# Generated by OpenFakeRAM
VERSION 5.7 ;
BUSBITCHARS "[]" ;
PROPERTYDEFINITIONS
  MACRO width INTEGER ;
  MACRO depth INTEGER ;
  MACRO banks INTEGER ;
END PROPERTYDEFINITIONS
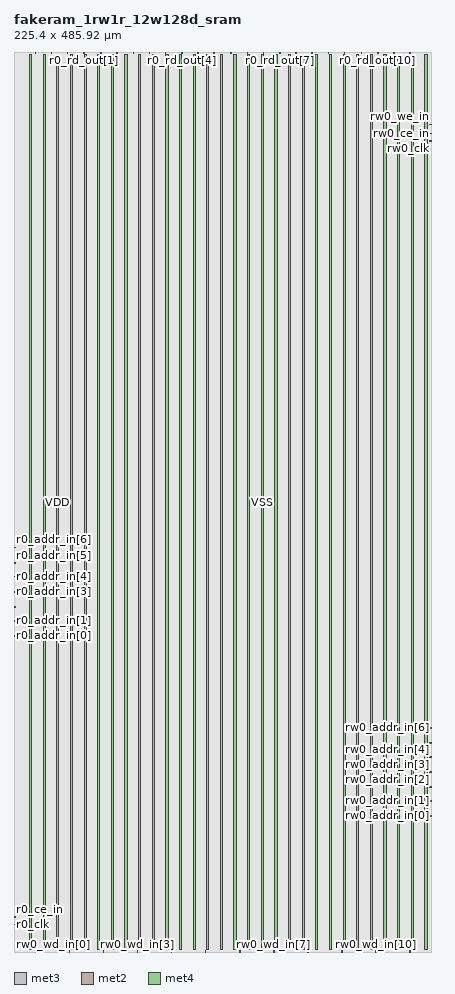
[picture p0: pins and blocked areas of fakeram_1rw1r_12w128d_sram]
MACRO fakeram_1rw1r_12w128d_sram
  PROPERTY width 12 ;
  PROPERTY depth 128 ;
  PROPERTY banks 1 ;
  FOREIGN fakeram_1rw1r_12w128d_sram 0 0 ;
  SYMMETRY X Y R90 ;
  SIZE 225.400 BY 485.920 ;
  CLASS BLOCK ;
  PIN r0_clk
    DIRECTION INPUT ;
    USE SIGNAL ;
    SHAPE ABUTMENT ;
    PORT
      LAYER met3 ;
      RECT 0.000 14.810 0.800 15.110 ;
    END
  END r0_clk
  PIN r0_ce_in
    DIRECTION INPUT ;
    USE SIGNAL ;
    SHAPE ABUTMENT ;
    PORT
      LAYER met3 ;
      RECT 0.000 18.890 0.800 19.190 ;
    END
  END r0_ce_in
  PIN r0_addr_in[0]
    DIRECTION INPUT ;
    USE SIGNAL ;
    SHAPE ABUTMENT ;
    PORT
      LAYER met3 ;
      RECT 0.000 170.530 0.800 170.830 ;
    END
  END r0_addr_in[0]
  PIN r0_addr_in[1]
    DIRECTION INPUT ;
    USE SIGNAL ;
    SHAPE ABUTMENT ;
    PORT
      LAYER met3 ;
      RECT 0.000 178.690 0.800 178.990 ;
    END
  END r0_addr_in[1]
  PIN r0_addr_in[2]
    DIRECTION INPUT ;
    USE SIGNAL ;
    SHAPE ABUTMENT ;
    PORT
      LAYER met3 ;
      RECT 0.000 186.170 0.800 186.470 ;
    END
  END r0_addr_in[2]
  PIN r0_addr_in[3]
    DIRECTION INPUT ;
    USE SIGNAL ;
    SHAPE ABUTMENT ;
    PORT
      LAYER met3 ;
      RECT 0.000 194.330 0.800 194.630 ;
    END
  END r0_addr_in[3]
  PIN r0_addr_in[4]
    DIRECTION INPUT ;
    USE SIGNAL ;
    SHAPE ABUTMENT ;
    PORT
      LAYER met3 ;
      RECT 0.000 202.490 0.800 202.790 ;
    END
  END r0_addr_in[4]
  PIN r0_addr_in[5]
    DIRECTION INPUT ;
    USE SIGNAL ;
    SHAPE ABUTMENT ;
    PORT
      LAYER met3 ;
      RECT 0.000 209.970 0.800 210.270 ;
    END
  END r0_addr_in[5]
  PIN r0_addr_in[6]
    DIRECTION INPUT ;
    USE SIGNAL ;
    SHAPE ABUTMENT ;
    PORT
      LAYER met3 ;
      RECT 0.000 218.130 0.800 218.430 ;
    END
  END r0_addr_in[6]
  PIN rw0_rd_out[0]
    DIRECTION OUTPUT ;
    USE SIGNAL ;
    SHAPE ABUTMENT ;
    PORT
      LAYER met2 ;
      RECT 11.350 485.120 11.650 485.920 ;
    END
  END rw0_rd_out[0]
  PIN r0_rd_out[0]
    DIRECTION OUTPUT ;
    USE SIGNAL ;
    SHAPE ABUTMENT ;
    PORT
      LAYER met2 ;
      RECT 20.090 485.120 20.390 485.920 ;
    END
  END r0_rd_out[0]
  PIN rw0_rd_out[1]
    DIRECTION OUTPUT ;
    USE SIGNAL ;
    SHAPE ABUTMENT ;
    PORT
      LAYER met2 ;
      RECT 28.830 485.120 29.130 485.920 ;
    END
  END rw0_rd_out[1]
  PIN r0_rd_out[1]
    DIRECTION OUTPUT ;
    USE SIGNAL ;
    SHAPE ABUTMENT ;
    PORT
      LAYER met2 ;
      RECT 37.570 485.120 37.870 485.920 ;
    END
  END r0_rd_out[1]
  PIN rw0_rd_out[2]
    DIRECTION OUTPUT ;
    USE SIGNAL ;
    SHAPE ABUTMENT ;
    PORT
      LAYER met2 ;
      RECT 46.770 485.120 47.070 485.920 ;
    END
  END rw0_rd_out[2]
  PIN r0_rd_out[2]
    DIRECTION OUTPUT ;
    USE SIGNAL ;
    SHAPE ABUTMENT ;
    PORT
      LAYER met2 ;
      RECT 55.510 485.120 55.810 485.920 ;
    END
  END r0_rd_out[2]
  PIN rw0_rd_out[3]
    DIRECTION OUTPUT ;
    USE SIGNAL ;
    SHAPE ABUTMENT ;
    PORT
      LAYER met2 ;
      RECT 64.250 485.120 64.550 485.920 ;
    END
  END rw0_rd_out[3]
  PIN r0_rd_out[3]
    DIRECTION OUTPUT ;
    USE SIGNAL ;
    SHAPE ABUTMENT ;
    PORT
      LAYER met2 ;
      RECT 72.990 485.120 73.290 485.920 ;
    END
  END r0_rd_out[3]
  PIN rw0_rd_out[4]
    DIRECTION OUTPUT ;
    USE SIGNAL ;
    SHAPE ABUTMENT ;
    PORT
      LAYER met2 ;
      RECT 81.730 485.120 82.030 485.920 ;
    END
  END rw0_rd_out[4]
  PIN r0_rd_out[4]
    DIRECTION OUTPUT ;
    USE SIGNAL ;
    SHAPE ABUTMENT ;
    PORT
      LAYER met2 ;
      RECT 90.470 485.120 90.770 485.920 ;
    END
  END r0_rd_out[4]
  PIN rw0_rd_out[5]
    DIRECTION OUTPUT ;
    USE SIGNAL ;
    SHAPE ABUTMENT ;
    PORT
      LAYER met2 ;
      RECT 99.210 485.120 99.510 485.920 ;
    END
  END rw0_rd_out[5]
  PIN r0_rd_out[5]
    DIRECTION OUTPUT ;
    USE SIGNAL ;
    SHAPE ABUTMENT ;
    PORT
      LAYER met2 ;
      RECT 107.950 485.120 108.250 485.920 ;
    END
  END r0_rd_out[5]
  PIN rw0_rd_out[6]
    DIRECTION OUTPUT ;
    USE SIGNAL ;
    SHAPE ABUTMENT ;
    PORT
      LAYER met2 ;
      RECT 117.150 485.120 117.450 485.920 ;
    END
  END rw0_rd_out[6]
  PIN r0_rd_out[6]
    DIRECTION OUTPUT ;
    USE SIGNAL ;
    SHAPE ABUTMENT ;
    PORT
      LAYER met2 ;
      RECT 125.890 485.120 126.190 485.920 ;
    END
  END r0_rd_out[6]
  PIN rw0_rd_out[7]
    DIRECTION OUTPUT ;
    USE SIGNAL ;
    SHAPE ABUTMENT ;
    PORT
      LAYER met2 ;
      RECT 134.630 485.120 134.930 485.920 ;
    END
  END rw0_rd_out[7]
  PIN r0_rd_out[7]
    DIRECTION OUTPUT ;
    USE SIGNAL ;
    SHAPE ABUTMENT ;
    PORT
      LAYER met2 ;
      RECT 143.370 485.120 143.670 485.920 ;
    END
  END r0_rd_out[7]
  PIN rw0_rd_out[8]
    DIRECTION OUTPUT ;
    USE SIGNAL ;
    SHAPE ABUTMENT ;
    PORT
      LAYER met2 ;
      RECT 152.110 485.120 152.410 485.920 ;
    END
  END rw0_rd_out[8]
  PIN r0_rd_out[8]
    DIRECTION OUTPUT ;
    USE SIGNAL ;
    SHAPE ABUTMENT ;
    PORT
      LAYER met2 ;
      RECT 160.850 485.120 161.150 485.920 ;
    END
  END r0_rd_out[8]
  PIN rw0_rd_out[9]
    DIRECTION OUTPUT ;
    USE SIGNAL ;
    SHAPE ABUTMENT ;
    PORT
      LAYER met2 ;
      RECT 169.590 485.120 169.890 485.920 ;
    END
  END rw0_rd_out[9]
  PIN r0_rd_out[9]
    DIRECTION OUTPUT ;
    USE SIGNAL ;
    SHAPE ABUTMENT ;
    PORT
      LAYER met2 ;
      RECT 178.330 485.120 178.630 485.920 ;
    END
  END r0_rd_out[9]
  PIN rw0_rd_out[10]
    DIRECTION OUTPUT ;
    USE SIGNAL ;
    SHAPE ABUTMENT ;
    PORT
      LAYER met2 ;
      RECT 187.530 485.120 187.830 485.920 ;
    END
  END rw0_rd_out[10]
  PIN r0_rd_out[10]
    DIRECTION OUTPUT ;
    USE SIGNAL ;
    SHAPE ABUTMENT ;
    PORT
      LAYER met2 ;
      RECT 196.270 485.120 196.570 485.920 ;
    END
  END r0_rd_out[10]
  PIN rw0_rd_out[11]
    DIRECTION OUTPUT ;
    USE SIGNAL ;
    SHAPE ABUTMENT ;
    PORT
      LAYER met2 ;
      RECT 205.010 485.120 205.310 485.920 ;
    END
  END rw0_rd_out[11]
  PIN r0_rd_out[11]
    DIRECTION OUTPUT ;
    USE SIGNAL ;
    SHAPE ABUTMENT ;
    PORT
      LAYER met2 ;
      RECT 213.750 485.120 214.050 485.920 ;
    END
  END r0_rd_out[11]
  PIN rw0_clk
    DIRECTION INPUT ;
    USE SIGNAL ;
    SHAPE ABUTMENT ;
    PORT
      LAYER met3 ;
      RECT 224.600 437.770 225.400 438.070 ;
    END
  END rw0_clk
  PIN rw0_ce_in
    DIRECTION INPUT ;
    USE SIGNAL ;
    SHAPE ABUTMENT ;
    PORT
      LAYER met3 ;
      RECT 224.600 441.850 225.400 442.150 ;
    END
  END rw0_ce_in
  PIN rw0_we_in
    DIRECTION INPUT ;
    USE SIGNAL ;
    SHAPE ABUTMENT ;
    PORT
      LAYER met3 ;
      RECT 224.600 446.610 225.400 446.910 ;
    END
  END rw0_we_in
  PIN rw0_addr_in[0]
    DIRECTION INPUT ;
    USE SIGNAL ;
    SHAPE ABUTMENT ;
    PORT
      LAYER met3 ;
      RECT 224.600 73.290 225.400 73.590 ;
    END
  END rw0_addr_in[0]
  PIN rw0_addr_in[1]
    DIRECTION INPUT ;
    USE SIGNAL ;
    SHAPE ABUTMENT ;
    PORT
      LAYER met3 ;
      RECT 224.600 81.450 225.400 81.750 ;
    END
  END rw0_addr_in[1]
  PIN rw0_addr_in[2]
    DIRECTION INPUT ;
    USE SIGNAL ;
    SHAPE ABUTMENT ;
    PORT
      LAYER met3 ;
      RECT 224.600 88.930 225.400 89.230 ;
    END
  END rw0_addr_in[2]
  PIN rw0_addr_in[3]
    DIRECTION INPUT ;
    USE SIGNAL ;
    SHAPE ABUTMENT ;
    PORT
      LAYER met3 ;
      RECT 224.600 97.090 225.400 97.390 ;
    END
  END rw0_addr_in[3]
  PIN rw0_addr_in[4]
    DIRECTION INPUT ;
    USE SIGNAL ;
    SHAPE ABUTMENT ;
    PORT
      LAYER met3 ;
      RECT 224.600 105.250 225.400 105.550 ;
    END
  END rw0_addr_in[4]
  PIN rw0_addr_in[5]
    DIRECTION INPUT ;
    USE SIGNAL ;
    SHAPE ABUTMENT ;
    PORT
      LAYER met3 ;
      RECT 224.600 112.730 225.400 113.030 ;
    END
  END rw0_addr_in[5]
  PIN rw0_addr_in[6]
    DIRECTION INPUT ;
    USE SIGNAL ;
    SHAPE ABUTMENT ;
    PORT
      LAYER met3 ;
      RECT 224.600 120.890 225.400 121.190 ;
    END
  END rw0_addr_in[6]
  PIN rw0_wd_in[0]
    DIRECTION INPUT ;
    USE SIGNAL ;
    SHAPE ABUTMENT ;
    PORT
      LAYER met2 ;
      RECT 11.350 0.000 11.650 0.800 ;
    END
  END rw0_wd_in[0]
  PIN rw0_wd_in[1]
    DIRECTION INPUT ;
    USE SIGNAL ;
    SHAPE ABUTMENT ;
    PORT
      LAYER met2 ;
      RECT 29.750 0.000 30.050 0.800 ;
    END
  END rw0_wd_in[1]
  PIN rw0_wd_in[2]
    DIRECTION INPUT ;
    USE SIGNAL ;
    SHAPE ABUTMENT ;
    PORT
      LAYER met2 ;
      RECT 48.150 0.000 48.450 0.800 ;
    END
  END rw0_wd_in[2]
  PIN rw0_wd_in[3]
    DIRECTION INPUT ;
    USE SIGNAL ;
    SHAPE ABUTMENT ;
    PORT
      LAYER met2 ;
      RECT 66.550 0.000 66.850 0.800 ;
    END
  END rw0_wd_in[3]
  PIN rw0_wd_in[4]
    DIRECTION INPUT ;
    USE SIGNAL ;
    SHAPE ABUTMENT ;
    PORT
      LAYER met2 ;
      RECT 84.950 0.000 85.250 0.800 ;
    END
  END rw0_wd_in[4]
  PIN rw0_wd_in[5]
    DIRECTION INPUT ;
    USE SIGNAL ;
    SHAPE ABUTMENT ;
    PORT
      LAYER met2 ;
      RECT 103.350 0.000 103.650 0.800 ;
    END
  END rw0_wd_in[5]
  PIN rw0_wd_in[6]
    DIRECTION INPUT ;
    USE SIGNAL ;
    SHAPE ABUTMENT ;
    PORT
      LAYER met2 ;
      RECT 121.750 0.000 122.050 0.800 ;
    END
  END rw0_wd_in[6]
  PIN rw0_wd_in[7]
    DIRECTION INPUT ;
    USE SIGNAL ;
    SHAPE ABUTMENT ;
    PORT
      LAYER met2 ;
      RECT 140.150 0.000 140.450 0.800 ;
    END
  END rw0_wd_in[7]
  PIN rw0_wd_in[8]
    DIRECTION INPUT ;
    USE SIGNAL ;
    SHAPE ABUTMENT ;
    PORT
      LAYER met2 ;
      RECT 158.550 0.000 158.850 0.800 ;
    END
  END rw0_wd_in[8]
  PIN rw0_wd_in[9]
    DIRECTION INPUT ;
    USE SIGNAL ;
    SHAPE ABUTMENT ;
    PORT
      LAYER met2 ;
      RECT 176.950 0.000 177.250 0.800 ;
    END
  END rw0_wd_in[9]
  PIN rw0_wd_in[10]
    DIRECTION INPUT ;
    USE SIGNAL ;
    SHAPE ABUTMENT ;
    PORT
      LAYER met2 ;
      RECT 195.350 0.000 195.650 0.800 ;
    END
  END rw0_wd_in[10]
  PIN rw0_wd_in[11]
    DIRECTION INPUT ;
    USE SIGNAL ;
    SHAPE ABUTMENT ;
    PORT
      LAYER met2 ;
      RECT 213.750 0.000 214.050 0.800 ;
    END
  END rw0_wd_in[11]
  PIN VSS
    DIRECTION INOUT ;
    USE GROUND ;
    PORT
      LAYER met4 ;
      RECT 15.720 1.600 16.920 484.320 ;
      RECT 30.440 1.600 31.640 484.320 ;
      RECT 45.160 1.600 46.360 484.320 ;
      RECT 59.880 1.600 61.080 484.320 ;
      RECT 74.600 1.600 75.800 484.320 ;
      RECT 89.320 1.600 90.520 484.320 ;
      RECT 104.040 1.600 105.240 484.320 ;
      RECT 118.760 1.600 119.960 484.320 ;
      RECT 133.480 1.600 134.680 484.320 ;
      RECT 148.200 1.600 149.400 484.320 ;
      RECT 162.920 1.600 164.120 484.320 ;
      RECT 177.640 1.600 178.840 484.320 ;
      RECT 192.360 1.600 193.560 484.320 ;
      RECT 207.080 1.600 208.280 484.320 ;
      RECT 221.800 1.600 223.000 484.320 ;
    END
  END VSS
  PIN VDD
    DIRECTION INOUT ;
    USE POWER ;
    PORT
      LAYER met4 ;
      RECT 8.360 1.600 9.560 484.320 ;
      RECT 23.080 1.600 24.280 484.320 ;
      RECT 37.800 1.600 39.000 484.320 ;
      RECT 52.520 1.600 53.720 484.320 ;
      RECT 67.240 1.600 68.440 484.320 ;
      RECT 81.960 1.600 83.160 484.320 ;
      RECT 96.680 1.600 97.880 484.320 ;
      RECT 111.400 1.600 112.600 484.320 ;
      RECT 126.120 1.600 127.320 484.320 ;
      RECT 140.840 1.600 142.040 484.320 ;
      RECT 155.560 1.600 156.760 484.320 ;
      RECT 170.280 1.600 171.480 484.320 ;
      RECT 185.000 1.600 186.200 484.320 ;
      RECT 199.720 1.600 200.920 484.320 ;
      RECT 214.440 1.600 215.640 484.320 ;
    END
  END VDD
  OBS
    LAYER met1 ;
    RECT 0 0 225.400 485.920 ;
    LAYER met2 ;
    RECT 0 0 225.400 485.920 ;
    LAYER met3 ;
    RECT 0 0 225.400 485.920 ;
    LAYER met4 ;
    RECT 0 0 225.400 485.920 ;
    LAYER OVERLAP ;
    RECT 0 0 225.400 485.920 ;
  END
END fakeram_1rw1r_12w128d_sram

END LIBRARY
